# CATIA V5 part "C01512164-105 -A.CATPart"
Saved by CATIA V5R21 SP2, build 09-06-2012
Part number: C01512164-105
Revision: ---
Description: PROPRIETARY NOTICE (do not delete / modify)  ***************************************************************************************************  LA SOCIETE EN COMMANDITE  AIRBUS CANADA  ("AIRBUS CANADA")  PAR  L'INTERMEDIAIRE  DE  SES  DIVISIONS  ET/OU  FILIALES  CORPORATIVES,  FOURNIT  LES PRESENTES  INFORMATIONS  AU  GOUVERNEMENT  A  TITRE CONFIDENTIEL. CES  INFORMATIONS ONT UNE TENEUR CONFIDENTIELLE,  AVEC DROITS DE PROPRIETE,  ET NOUS LES CONSIDERONS  EXCLUS  DE   L'APPLICATION  DE  LA LOI SUR L'ACCES A L'INFORMATION  (CANADA),  LES  LOIS  SUR  L'ACCES  A  L'INFORMATION  EUROPEENNES,  LE FREEDOM OF INFORMATION ACT (ETATS-UNIS) ET D'AUTRES LOIS SEMBLABLES. ELLES  PEUVENT  AUSSI  CONSTITUER DES SECRETS INDUSTRIELS DE NOTRE SOCIETE OU DE TIERCES PARTIES. LA DIVULGATION  PUBLIQUE  DE CES  INFORMATIONS NUIRAIT A AIRBUS CANADA OU A DES TIERCES PARTIES.  CES INFORMATIONS PEUVENT EGALEMENT CONTENIR  DES DONNEES QUI SONT CONTROLEE PAR DES LOIS DE CONTROLE DES EXPORTATIONS DU CANADA, L’EUROPE OU LES  ETATS-  UNIS. TOUTE EXPORTATION OU REEXPORTATION DE DONNEES CONTROLEES SANS AUTORISATION EST STRICTEMENT INTERDITE.  TOUTE INTENTION DE LES DIVULGUER EN TOUT OU EN PARTIE DEVRA ETRE SIGNIFIEE A L'AVANCE ET PAR ECRIT AU VICE-  PRESIDENT, SERVICES JURIDIQUES ET CONFORMITE ET SECRETAIRE CORPORATIF D'AIRBUS CANADA.    AIRBUS CANADA LIMITED PARTNERSHIP  ("AIRBUS CANADA"),  BY ITS AFFILIATES AND/OR SUBSIDIARIES, PROVIDES THIS  INFORMATION TO THE GOVERNMENT IN CONFIDENCE. THIS IS PROPRIETARY CONFIDENTIAL INFORMATION WHICH WE CONSIDER  EXCLUDED  FROM  THE  APPLICATION OF THE ACCESS TO INFORMATION ACT (CANADA),  THE FREEDOM OF INFORMATION ACT  (U.S.A.),  THE ACCESS TO INFORMATION LAWS IN EUROPE, AND OTHER SIMILAR LEGISLATION. AND MAY ALSO CONSTITUTE  TRADE SECRETS OF OUR  COMPANY OR THIRD PARTIES.  PUBLIC  RELEASE  OF  THIS INFORMATION  WOULD BE HARMFUL TO  AIRBUS CANADA OR THIRD PARTIES.  THIS  INFORMATION  MAY  ALSO  CONTAIN DATA THAT IS CONTROLLED BY CANADIAN,  EUROPEAN, OR U.S.A. EXPORT CONTROL LAWS. ANY UNAUTHORIZED EXPORT OR RE-EXPORT OF ANY EXPORT CONTROLLED DATA  IS STRICTLY PROHIBITED  ANY INTENTION TO DISCLOSE SUCH INFORMATION,  OR  PART THEREOF,  MUST BE NOTIFIED IN  ADVANCE AND IN WRITING TO THE VICE PRESIDENT, LEGAL AND COMPLIANCE AND CORPORATE SECRETARY OF AIRBUS CANADA.        LES RENSEIGNEMENTS,  LES DONNEES  ET  DESSINS  TECHNIQUES  DIVULGUES  DANS  LES PRESENTES SONT LA PROPRIETE  EXCLUSIVE DE LA SOCIETE EN COMMANDITE AIRBUS CANADA ("AIRBUS CANADA") OU COMPORTENT DES DROITS DE PROPRIETE  APPARTENANT  A  AUTRUI ET NE PEUVENT ETRE DIVULGUES  A  QUICONQUE  NI  UTILISES PAR QUI QUE CE SOIT SANS LE  CONSENTEMENT  ECRIT  D’AIRBUS  CANADA.  LE DETENTEUR DES  PRESENTES  S'ENGAGE, DANS TOUTES CIRCONSTANCES, A  GARDER CONFIDENTIELS LES DONNEES ET DESSINS TECHNIQUES QU'ELLES CONTIENNENT.   CE QUI PRECEDE NE S'APPLIQUE  PAS  AUX PERSONNES  QUI  ONT DES DROITS DE PROPRIETE SUR CES RENSEIGNEMENTS,  DONNEES TECHNIQUES ET DESSINS  DANS LA MESURE OU CES DROITS EXISTENT.    THE INFORMATION,  TECHNICAL DATA  AND  DESIGNS DISCLOSED HEREIN ARE THE EXCLUSIVE PROPERTY OF AIRBUS CANADA  LIMITED PARTNERSHIP  ("AIRBUS CANADA")  OR  CONTAIN PROPRIETARY RIGHTS OF OTHERS  AND ARE NOT TO BE USED OR  DISCLOSED  TO  OTHERS WITHOUT THE WRITTEN CONSENT OF AIRBUS CANADA.  THE RECIPIENT OF THIS DOCUMENT, BY ITS  RETENTION  AND  USE  AGREES TO  HOLD  IN  CONFIDENCE  THE  TECHNICAL DATA AND DESIGNS CONTAINED HEREIN. THE  FOREGOING SHALL NOT APPLY TO PERSONS HAVING PROPRIETARY RIGHTS TO SUCH INFORMATION,  TECHNICAL DATA OR SUCH  DESIGNS TO THE EXTENT THAT SUCH RIGHTS EXIST.    Copyright 2020 Airbus Canada Limited Partnership. All Rights Reserved.  ***********************************
Property "Title": "PIN, TRIG, PASS SVCE DR"
Property "Dataset Type": "DETAIL"
Property "Supplier Name And CAGE Code": "AIRBUS CANADA LIMITED PARTNERSHIP L0J48"
Property "Material Form": "BAR - ROUND"
Property "Finish Code": "S010"
Property "PCCN": "2"
Property "Major Supplier Code": "LP"
Property "3D Only": "Y"
Property "Organization": "DESIGN"
Property "Design Authority Program": "BD-500"
Property "Color Coded": "N/A"
Property "Thickness": 0
Property "Inside Diameter": 0
Property "Outside Diameter": 0.5
Property "Length": 0
Property "Width": 0
Property "Wall": 0
Property "Wire Gauge": "-"
Property "Alloy": "15-5PH"
Property "Final Condition": "H1025"
Property "Density": "N/A"
Property "Form": "N/A"
Property "Grade/Composition": "N/A"
Property "Material Class": "N/A"
Property "Mesh Cell Size": "N/A"
Property "Standard Spec Die": "N/A"
Property "Type": "N/A"
Property "Style": "N/A"
Property "MFG Process": "MACHINED"
Property "Material Specification Production": "AMS5659"
Property "Material Description Production": "CRES"
Property "Dimensions": "DIMENSIONS ARE IN INCHES"
Property "Roughness": "ALL MACHINED SURFACES 125 Ra MAX"
Property "Eng. Tolerances": "LINEAR .XX= +/-.03; .XXX= +/-.010; ANGULAR= +/-0.5 DEG"
Property "Tool Design Tolerances": "LINEAR .X= +/-.06; .XX= +/-.015; .XXX= +/-.005; .XXXX= +/-.001; ANGULAR= +/-0.5 DEG"
Property "Project": "BA"
Publications: "PartBody", "Extract.1_Datum_A", "Extract.1_Datum_B", "Extract.2_Datum_B"
Material "CRES-PH-15-5-BAR": density 7833.41 kg/m3
Bounding box of the stored display mesh (mm): x 0 to 25.4, y -3.134 to 3.134, z -3.134 to 3.132
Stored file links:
  C:\Users\CQQZ006\Desktop\A220钢钛件\舱门\C01512164-105\C01512164-105 -A.CATPart
  I:\Standard\Materials\Textures\steel100.jpeg

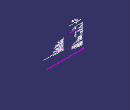
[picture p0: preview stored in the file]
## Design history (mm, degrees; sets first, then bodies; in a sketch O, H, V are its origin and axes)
Parameters
  Pad_Dia = 13.97 mm
  Pad_Thk = 5.461 mm
  Neck_Dia = 8.6868 mm
  Thread_Dia = 11.1125 mm
  Pin_Length = 37.719 mm
  Slot_Width = 2.4257 mm
  Slot_Depth = 1.778 mm
  Slot_Length = 20.32 mm
AxisSystem1 "Absolute Axis System": origin (0, 0, 0), X (1, 0, 0), Y (0, 1, 0), Z (0, 0, 1)
Part_3D_Annotations1 "CATTPSSet"
Set1 "Geometrical Set for 3D Annotations"
  Set2 "No Show Geometry"
    Extract1 "Extract.1_Datum_A": ExtractElem face of Shaft1 from Sketch1.L2
    Extract2 "Extract.1_Datum_B": ExtractElem face of Shaft1 from Sketch1.L3
    Extract3 "Extract.2_Datum_B": ExtractElem face of Shaft1 from Sketch1.L3
Set3 "Construction_Geometry"
  MultiSel1
Set4 "References"
  DatumSurface1 "C01512164-001"
Body1 (main body)
  Sketch1 on XY plane of AxisSystem1, origin (0, 0, 0), H (1, 0, 0), V (0, 1, 0)
    construction line L1 (25.4, 0) -> (0, 0)
    line L2 (0.9886, 3.1337) -> (25.4, 3.1337)
    line L3 (25.4, 3.1337) -> (25.4, 0)
    axis line L4 (5.715, -8.3116) -> (5.715, 4.318)
    arc A1 centre (5.461, 0) radius 5.461 from (0.9886, 3.1337) to (0, 0) ccw
    point P5 (5.461, 0)
    distance L1 L2 = 3.1337
    radius A1 = 5.461
    distance L3 V = 25.4
    horizontal: L1 H, L2 H
    vertical: L3 V
    coincidence: H L1, P5 L1
    tangency: A1 V
  Shaft1: profile Sketch1, axis edge [XY plane of AxisSystem1 | ZX plane of AxisSystem1], angle 360
  Body2
    Sketch2 on zx-plane, origin (0, 0, 0), H (-1, 0, 0), V (0, 0, 1)
      line L1 (-25.4, 1.8193) -> (-25.4, 6.8993)
      line L2 (-25.4, 6.8993) -> (-3.81, 6.8993)
      line L3 (-3.81, 6.8993) -> (-3.81, 5.6293)
      line L4 (-7.62, 1.8193) -> (-25.4, 1.8193)
      arc A1 centre (-7.62, 5.6293) radius 3.81 from (-7.62, 1.8193) to (-3.81, 5.6293) ccw
      reference intersected line E1 (-25.4, -3.175) -> (-25.4, 3.175) from face of Shaft1 from Sketch1.L3
      construction line L5 (-20.8512, 1.9939) -> (-19.8941, 1.9939)
      construction line L6 (-19.8941, 1.9939) -> (-19.8941, 3.302)
      construction line L7 (-19.8941, 3.302) -> (-20.8512, 3.302)
      construction line L8 (-20.8512, 3.302) -> (-20.8512, 1.9939)
      construction line L9 (-31.1069, -3.1337) -> (11.8848, -3.1337)
      radius A1 = 3.81
      distance L4 L2 = 5.08
      distance L1 L3 = 21.59
      distance L7 H = 3.302
      distance L5 H = 1.9939
      distance H L9 = 3.1337
      distance L9 L4 = 4.953
      tangency: A1 L4, A1 L3
      vertical: L3 V, L6 V, L8 V
      coincidence: L1 E1
      horizontal: L5 H, L7 H
    Pocket1: profile Sketch2, direction (0, -1, 0), length 0.762, mirrored extent
    Fillet1: radius 0.254, on edge [face of Pocket1 from Sketch2.L4 | start face of Pocket1]; edge [end face of Pocket1 | face of Pocket1 from Sketch2.L4]
  Assemble1: tool Body2
  Body3
    Sketch3 on face of Shaft1 from Sketch1.L3, origin (25.4, 0, 0), H (0, 1, 0), V (0, 0, 1)
      line L1 (3.1337, 1.0287) -> (-3.1337, 1.0287)
      line L2 (-3.1337, -1.0287) -> (3.1337, -1.0287)
      line L3 (-3.1337, 1.0287) -> (-3.1337, -1.0287)
      line L4 (3.1337, 1.0287) -> (3.1337, -1.0287)
      reference projected point E1 (3.1337, 0) from vertex [element of Sketch1 | element of Sketch1]
      distance L2 L1 = 2.0574
      perpendicularity: L3 L2, L4 L2
      coincidence: L4 E1
      symmetry: L3 L4 V, L1 L2 H
    Pocket2: profile Sketch3, direction (-1, 0, 0), length 3.175
    Fillet2: radius 0.254, on edge [end face of Pocket2 | face of Pocket2 from Sketch3.L1]; edge [end face of Pocket2 | face of Pocket2 from Sketch3.L2]
  Assemble2: tool Body3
